VERSION 5.4 ;
NAMESCASESENSITIVE ON ;
BUSBITCHARS "[]" ;
DIVIDERCHAR "/" ;
UNITS
  DATABASE MICRONS 2000 ;
END UNITS
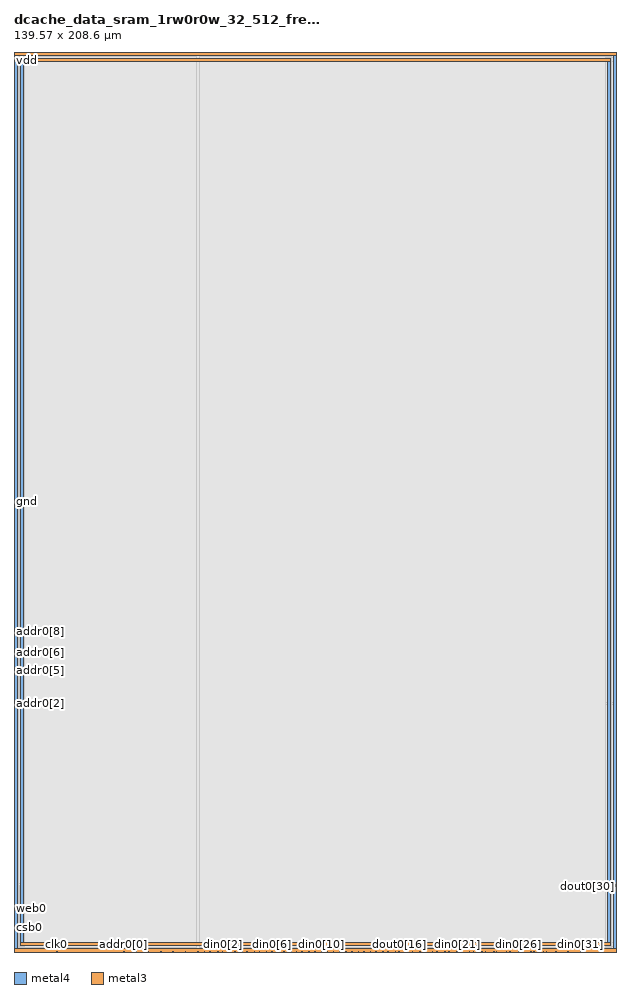
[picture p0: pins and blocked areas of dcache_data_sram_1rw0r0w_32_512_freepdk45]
MACRO dcache_data_sram_1rw0r0w_32_512_freepdk45
   CLASS BLOCK ;
   SIZE 139.57 BY 208.6 ;
   SYMMETRY X Y R90 ;
   PIN din0[0]
      DIRECTION INPUT ;
      PORT
         LAYER metal4 ;
         RECT  42.5575 0.0 42.6975 0.14 ;
      END
   END din0[0]
   PIN din0[1]
      DIRECTION INPUT ;
      PORT
         LAYER metal4 ;
         RECT  45.4175 0.0 45.5575 0.14 ;
      END
   END din0[1]
   PIN din0[2]
      DIRECTION INPUT ;
      PORT
         LAYER metal4 ;
         RECT  48.2775 0.0 48.4175 0.14 ;
      END
   END din0[2]
   PIN din0[3]
      DIRECTION INPUT ;
      PORT
         LAYER metal4 ;
         RECT  51.1375 0.0 51.2775 0.14 ;
      END
   END din0[3]
   PIN din0[4]
      DIRECTION INPUT ;
      PORT
         LAYER metal4 ;
         RECT  53.9975 0.0 54.1375 0.14 ;
      END
   END din0[4]
   PIN din0[5]
      DIRECTION INPUT ;
      PORT
         LAYER metal4 ;
         RECT  56.8575 0.0 56.9975 0.14 ;
      END
   END din0[5]
   PIN din0[6]
      DIRECTION INPUT ;
      PORT
         LAYER metal4 ;
         RECT  59.7175 0.0 59.8575 0.14 ;
      END
   END din0[6]
   PIN din0[7]
      DIRECTION INPUT ;
      PORT
         LAYER metal4 ;
         RECT  62.5775 0.0 62.7175 0.14 ;
      END
   END din0[7]
   PIN din0[8]
      DIRECTION INPUT ;
      PORT
         LAYER metal4 ;
         RECT  65.4375 0.0 65.5775 0.14 ;
      END
   END din0[8]
   PIN din0[9]
      DIRECTION INPUT ;
      PORT
         LAYER metal4 ;
         RECT  68.2975 0.0 68.4375 0.14 ;
      END
   END din0[9]
   PIN din0[10]
      DIRECTION INPUT ;
      PORT
         LAYER metal4 ;
         RECT  71.1575 0.0 71.2975 0.14 ;
      END
   END din0[10]
   PIN din0[11]
      DIRECTION INPUT ;
      PORT
         LAYER metal4 ;
         RECT  74.0175 0.0 74.1575 0.14 ;
      END
   END din0[11]
   PIN din0[12]
      DIRECTION INPUT ;
      PORT
         LAYER metal4 ;
         RECT  76.8775 0.0 77.0175 0.14 ;
      END
   END din0[12]
   PIN din0[13]
      DIRECTION INPUT ;
      PORT
         LAYER metal4 ;
         RECT  79.7375 0.0 79.8775 0.14 ;
      END
   END din0[13]
   PIN din0[14]
      DIRECTION INPUT ;
      PORT
         LAYER metal4 ;
         RECT  82.5975 0.0 82.7375 0.14 ;
      END
   END din0[14]
   PIN din0[15]
      DIRECTION INPUT ;
      PORT
         LAYER metal4 ;
         RECT  85.4575 0.0 85.5975 0.14 ;
      END
   END din0[15]
   PIN din0[16]
      DIRECTION INPUT ;
      PORT
         LAYER metal4 ;
         RECT  88.3175 0.0 88.4575 0.14 ;
      END
   END din0[16]
   PIN din0[17]
      DIRECTION INPUT ;
      PORT
         LAYER metal4 ;
         RECT  91.1775 0.0 91.3175 0.14 ;
      END
   END din0[17]
   PIN din0[18]
      DIRECTION INPUT ;
      PORT
         LAYER metal4 ;
         RECT  94.0375 0.0 94.1775 0.14 ;
      END
   END din0[18]
   PIN din0[19]
      DIRECTION INPUT ;
      PORT
         LAYER metal4 ;
         RECT  96.8975 0.0 97.0375 0.14 ;
      END
   END din0[19]
   PIN din0[20]
      DIRECTION INPUT ;
      PORT
         LAYER metal4 ;
         RECT  99.7575 0.0 99.8975 0.14 ;
      END
   END din0[20]
   PIN din0[21]
      DIRECTION INPUT ;
      PORT
         LAYER metal4 ;
         RECT  102.6175 0.0 102.7575 0.14 ;
      END
   END din0[21]
   PIN din0[22]
      DIRECTION INPUT ;
      PORT
         LAYER metal4 ;
         RECT  105.4775 0.0 105.6175 0.14 ;
      END
   END din0[22]
   PIN din0[23]
      DIRECTION INPUT ;
      PORT
         LAYER metal4 ;
         RECT  108.3375 0.0 108.4775 0.14 ;
      END
   END din0[23]
   PIN din0[24]
      DIRECTION INPUT ;
      PORT
         LAYER metal4 ;
         RECT  111.1975 0.0 111.3375 0.14 ;
      END
   END din0[24]
   PIN din0[25]
      DIRECTION INPUT ;
      PORT
         LAYER metal4 ;
         RECT  114.0575 0.0 114.1975 0.14 ;
      END
   END din0[25]
   PIN din0[26]
      DIRECTION INPUT ;
      PORT
         LAYER metal4 ;
         RECT  116.9175 0.0 117.0575 0.14 ;
      END
   END din0[26]
   PIN din0[27]
      DIRECTION INPUT ;
      PORT
         LAYER metal4 ;
         RECT  119.7775 0.0 119.9175 0.14 ;
      END
   END din0[27]
   PIN din0[28]
      DIRECTION INPUT ;
      PORT
         LAYER metal4 ;
         RECT  122.6375 0.0 122.7775 0.14 ;
      END
   END din0[28]
   PIN din0[29]
      DIRECTION INPUT ;
      PORT
         LAYER metal4 ;
         RECT  125.4975 0.0 125.6375 0.14 ;
      END
   END din0[29]
   PIN din0[30]
      DIRECTION INPUT ;
      PORT
         LAYER metal4 ;
         RECT  128.3575 0.0 128.4975 0.14 ;
      END
   END din0[30]
   PIN din0[31]
      DIRECTION INPUT ;
      PORT
         LAYER metal4 ;
         RECT  131.2175 0.0 131.3575 0.14 ;
      END
   END din0[31]
   PIN addr0[0]
      DIRECTION INPUT ;
      PORT
         LAYER metal4 ;
         RECT  25.3975 0.0 25.5375 0.14 ;
      END
   END addr0[0]
   PIN addr0[1]
      DIRECTION INPUT ;
      PORT
         LAYER metal4 ;
         RECT  28.2575 0.0 28.3975 0.14 ;
      END
   END addr0[1]
   PIN addr0[2]
      DIRECTION INPUT ;
      PORT
         LAYER metal3 ;
         RECT  0.0 57.5725 0.14 57.7125 ;
      END
   END addr0[2]
   PIN addr0[3]
      DIRECTION INPUT ;
      PORT
         LAYER metal3 ;
         RECT  0.0 60.3025 0.14 60.4425 ;
      END
   END addr0[3]
   PIN addr0[4]
      DIRECTION INPUT ;
      PORT
         LAYER metal3 ;
         RECT  0.0 62.5125 0.14 62.6525 ;
      END
   END addr0[4]
   PIN addr0[5]
      DIRECTION INPUT ;
      PORT
         LAYER metal3 ;
         RECT  0.0 65.2425 0.14 65.3825 ;
      END
   END addr0[5]
   PIN addr0[6]
      DIRECTION INPUT ;
      PORT
         LAYER metal3 ;
         RECT  0.0 67.4525 0.14 67.5925 ;
      END
   END addr0[6]
   PIN addr0[7]
      DIRECTION INPUT ;
      PORT
         LAYER metal3 ;
         RECT  0.0 70.1825 0.14 70.3225 ;
      END
   END addr0[7]
   PIN addr0[8]
      DIRECTION INPUT ;
      PORT
         LAYER metal3 ;
         RECT  0.0 72.3925 0.14 72.5325 ;
      END
   END addr0[8]
   PIN csb0
      DIRECTION INPUT ;
      PORT
         LAYER metal3 ;
         RECT  0.0 7.3925 0.14 7.5325 ;
      END
   END csb0
   PIN web0
      DIRECTION INPUT ;
      PORT
         LAYER metal3 ;
         RECT  0.0 10.1225 0.14 10.2625 ;
      END
   END web0
   PIN clk0
      DIRECTION INPUT ;
      PORT
         LAYER metal4 ;
         RECT  9.84 0.0 9.98 0.14 ;
      END
   END clk0
   PIN wmask0[0]
      DIRECTION INPUT ;
      PORT
         LAYER metal4 ;
         RECT  31.1175 0.0 31.2575 0.14 ;
      END
   END wmask0[0]
   PIN wmask0[1]
      DIRECTION INPUT ;
      PORT
         LAYER metal4 ;
         RECT  33.9775 0.0 34.1175 0.14 ;
      END
   END wmask0[1]
   PIN wmask0[2]
      DIRECTION INPUT ;
      PORT
         LAYER metal4 ;
         RECT  36.8375 0.0 36.9775 0.14 ;
      END
   END wmask0[2]
   PIN wmask0[3]
      DIRECTION INPUT ;
      PORT
         LAYER metal4 ;
         RECT  39.6975 0.0 39.8375 0.14 ;
      END
   END wmask0[3]
   PIN dout0[0]
      DIRECTION OUTPUT ;
      PORT
         LAYER metal4 ;
         RECT  44.06 0.0 44.2 0.14 ;
      END
   END dout0[0]
   PIN dout0[1]
      DIRECTION OUTPUT ;
      PORT
         LAYER metal4 ;
         RECT  47.1925 0.0 47.3325 0.14 ;
      END
   END dout0[1]
   PIN dout0[2]
      DIRECTION OUTPUT ;
      PORT
         LAYER metal4 ;
         RECT  50.0125 0.0 50.1525 0.14 ;
      END
   END dout0[2]
   PIN dout0[3]
      DIRECTION OUTPUT ;
      PORT
         LAYER metal4 ;
         RECT  52.8325 0.0 52.9725 0.14 ;
      END
   END dout0[3]
   PIN dout0[4]
      DIRECTION OUTPUT ;
      PORT
         LAYER metal4 ;
         RECT  55.6525 0.0 55.7925 0.14 ;
      END
   END dout0[4]
   PIN dout0[5]
      DIRECTION OUTPUT ;
      PORT
         LAYER metal4 ;
         RECT  58.4725 0.0 58.6125 0.14 ;
      END
   END dout0[5]
   PIN dout0[6]
      DIRECTION OUTPUT ;
      PORT
         LAYER metal4 ;
         RECT  61.2925 0.0 61.4325 0.14 ;
      END
   END dout0[6]
   PIN dout0[7]
      DIRECTION OUTPUT ;
      PORT
         LAYER metal4 ;
         RECT  64.1125 0.0 64.2525 0.14 ;
      END
   END dout0[7]
   PIN dout0[8]
      DIRECTION OUTPUT ;
      PORT
         LAYER metal4 ;
         RECT  66.62 0.0 66.76 0.14 ;
      END
   END dout0[8]
   PIN dout0[9]
      DIRECTION OUTPUT ;
      PORT
         LAYER metal4 ;
         RECT  69.7525 0.0 69.8925 0.14 ;
      END
   END dout0[9]
   PIN dout0[10]
      DIRECTION OUTPUT ;
      PORT
         LAYER metal4 ;
         RECT  72.5725 0.0 72.7125 0.14 ;
      END
   END dout0[10]
   PIN dout0[11]
      DIRECTION OUTPUT ;
      PORT
         LAYER metal4 ;
         RECT  75.3925 0.0 75.5325 0.14 ;
      END
   END dout0[11]
   PIN dout0[12]
      DIRECTION OUTPUT ;
      PORT
         LAYER metal4 ;
         RECT  78.2125 0.0 78.3525 0.14 ;
      END
   END dout0[12]
   PIN dout0[13]
      DIRECTION OUTPUT ;
      PORT
         LAYER metal4 ;
         RECT  81.0325 0.0 81.1725 0.14 ;
      END
   END dout0[13]
   PIN dout0[14]
      DIRECTION OUTPUT ;
      PORT
         LAYER metal4 ;
         RECT  83.8525 0.0 83.9925 0.14 ;
      END
   END dout0[14]
   PIN dout0[15]
      DIRECTION OUTPUT ;
      PORT
         LAYER metal4 ;
         RECT  86.6725 0.0 86.8125 0.14 ;
      END
   END dout0[15]
   PIN dout0[16]
      DIRECTION OUTPUT ;
      PORT
         LAYER metal4 ;
         RECT  89.18 0.0 89.32 0.14 ;
      END
   END dout0[16]
   PIN dout0[17]
      DIRECTION OUTPUT ;
      PORT
         LAYER metal4 ;
         RECT  92.3125 0.0 92.4525 0.14 ;
      END
   END dout0[17]
   PIN dout0[18]
      DIRECTION OUTPUT ;
      PORT
         LAYER metal4 ;
         RECT  95.1325 0.0 95.2725 0.14 ;
      END
   END dout0[18]
   PIN dout0[19]
      DIRECTION OUTPUT ;
      PORT
         LAYER metal4 ;
         RECT  97.9525 0.0 98.0925 0.14 ;
      END
   END dout0[19]
   PIN dout0[20]
      DIRECTION OUTPUT ;
      PORT
         LAYER metal4 ;
         RECT  100.7725 0.0 100.9125 0.14 ;
      END
   END dout0[20]
   PIN dout0[21]
      DIRECTION OUTPUT ;
      PORT
         LAYER metal4 ;
         RECT  103.5925 0.0 103.7325 0.14 ;
      END
   END dout0[21]
   PIN dout0[22]
      DIRECTION OUTPUT ;
      PORT
         LAYER metal4 ;
         RECT  106.4125 0.0 106.5525 0.14 ;
      END
   END dout0[22]
   PIN dout0[23]
      DIRECTION OUTPUT ;
      PORT
         LAYER metal4 ;
         RECT  109.2325 0.0 109.3725 0.14 ;
      END
   END dout0[23]
   PIN dout0[24]
      DIRECTION OUTPUT ;
      PORT
         LAYER metal4 ;
         RECT  111.74 0.0 111.88 0.14 ;
      END
   END dout0[24]
   PIN dout0[25]
      DIRECTION OUTPUT ;
      PORT
         LAYER metal4 ;
         RECT  114.8725 0.0 115.0125 0.14 ;
      END
   END dout0[25]
   PIN dout0[26]
      DIRECTION OUTPUT ;
      PORT
         LAYER metal4 ;
         RECT  117.6925 0.0 117.8325 0.14 ;
      END
   END dout0[26]
   PIN dout0[27]
      DIRECTION OUTPUT ;
      PORT
         LAYER metal4 ;
         RECT  120.5125 0.0 120.6525 0.14 ;
      END
   END dout0[27]
   PIN dout0[28]
      DIRECTION OUTPUT ;
      PORT
         LAYER metal4 ;
         RECT  123.3325 0.0 123.4725 0.14 ;
      END
   END dout0[28]
   PIN dout0[29]
      DIRECTION OUTPUT ;
      PORT
         LAYER metal3 ;
         RECT  139.43 15.555 139.57 15.695 ;
      END
   END dout0[29]
   PIN dout0[30]
      DIRECTION OUTPUT ;
      PORT
         LAYER metal3 ;
         RECT  139.43 15.085 139.57 15.225 ;
      END
   END dout0[30]
   PIN dout0[31]
      DIRECTION OUTPUT ;
      PORT
         LAYER metal3 ;
         RECT  139.43 15.32 139.57 15.46 ;
      END
   END dout0[31]
   PIN vdd
      DIRECTION INOUT ;
      USE POWER ; 
      SHAPE ABUTMENT ; 
      PORT
         LAYER metal4 ;
         RECT  138.87 0.0 139.57 208.6 ;
         LAYER metal3 ;
         RECT  0.0 0.0 139.57 0.7 ;
         LAYER metal3 ;
         RECT  0.0 207.9 139.57 208.6 ;
         LAYER metal4 ;
         RECT  0.0 0.0 0.7 208.6 ;
      END
   END vdd
   PIN gnd
      DIRECTION INOUT ;
      USE GROUND ; 
      SHAPE ABUTMENT ; 
      PORT
         LAYER metal3 ;
         RECT  1.4 1.4 138.17 2.1 ;
         LAYER metal3 ;
         RECT  1.4 206.5 138.17 207.2 ;
         LAYER metal4 ;
         RECT  1.4 1.4 2.1 207.2 ;
         LAYER metal4 ;
         RECT  137.47 1.4 138.17 207.2 ;
      END
   END gnd
   OBS
   LAYER  metal1 ;
      RECT  0.14 0.14 139.43 208.46 ;
   LAYER  metal2 ;
      RECT  0.14 0.14 139.43 208.46 ;
   LAYER  metal3 ;
      RECT  0.28 57.4325 139.43 57.8525 ;
      RECT  0.14 57.8525 0.28 60.1625 ;
      RECT  0.14 60.5825 0.28 62.3725 ;
      RECT  0.14 62.7925 0.28 65.1025 ;
      RECT  0.14 65.5225 0.28 67.3125 ;
      RECT  0.14 67.7325 0.28 70.0425 ;
      RECT  0.14 70.4625 0.28 72.2525 ;
      RECT  0.14 7.6725 0.28 9.9825 ;
      RECT  0.14 10.4025 0.28 57.4325 ;
      RECT  0.28 15.415 139.29 15.835 ;
      RECT  0.28 15.835 139.29 57.4325 ;
      RECT  139.29 15.835 139.43 57.4325 ;
      RECT  0.14 0.84 0.28 7.2525 ;
      RECT  139.29 0.84 139.43 14.945 ;
      RECT  0.14 72.6725 0.28 207.76 ;
      RECT  0.28 0.84 1.26 1.26 ;
      RECT  0.28 1.26 1.26 2.24 ;
      RECT  0.28 2.24 1.26 15.415 ;
      RECT  1.26 0.84 138.31 1.26 ;
      RECT  1.26 2.24 138.31 15.415 ;
      RECT  138.31 0.84 139.29 1.26 ;
      RECT  138.31 1.26 139.29 2.24 ;
      RECT  138.31 2.24 139.29 15.415 ;
      RECT  0.28 57.8525 1.26 206.36 ;
      RECT  0.28 206.36 1.26 207.34 ;
      RECT  0.28 207.34 1.26 207.76 ;
      RECT  1.26 57.8525 138.31 206.36 ;
      RECT  1.26 207.34 138.31 207.76 ;
      RECT  138.31 57.8525 139.43 206.36 ;
      RECT  138.31 206.36 139.43 207.34 ;
      RECT  138.31 207.34 139.43 207.76 ;
   LAYER  metal4 ;
      RECT  42.2775 0.42 42.9775 208.46 ;
      RECT  125.9175 0.14 128.0775 0.42 ;
      RECT  128.7775 0.14 130.9375 0.42 ;
      RECT  25.8175 0.14 27.9775 0.42 ;
      RECT  10.26 0.14 25.1175 0.42 ;
      RECT  28.6775 0.14 30.8375 0.42 ;
      RECT  31.5375 0.14 33.6975 0.42 ;
      RECT  34.3975 0.14 36.5575 0.42 ;
      RECT  37.2575 0.14 39.4175 0.42 ;
      RECT  40.1175 0.14 42.2775 0.42 ;
      RECT  42.9775 0.14 43.78 0.42 ;
      RECT  44.48 0.14 45.1375 0.42 ;
      RECT  45.8375 0.14 46.9125 0.42 ;
      RECT  47.6125 0.14 47.9975 0.42 ;
      RECT  48.6975 0.14 49.7325 0.42 ;
      RECT  50.4325 0.14 50.8575 0.42 ;
      RECT  51.5575 0.14 52.5525 0.42 ;
      RECT  53.2525 0.14 53.7175 0.42 ;
      RECT  54.4175 0.14 55.3725 0.42 ;
      RECT  56.0725 0.14 56.5775 0.42 ;
      RECT  57.2775 0.14 58.1925 0.42 ;
      RECT  58.8925 0.14 59.4375 0.42 ;
      RECT  60.1375 0.14 61.0125 0.42 ;
      RECT  61.7125 0.14 62.2975 0.42 ;
      RECT  62.9975 0.14 63.8325 0.42 ;
      RECT  64.5325 0.14 65.1575 0.42 ;
      RECT  65.8575 0.14 66.34 0.42 ;
      RECT  67.04 0.14 68.0175 0.42 ;
      RECT  68.7175 0.14 69.4725 0.42 ;
      RECT  70.1725 0.14 70.8775 0.42 ;
      RECT  71.5775 0.14 72.2925 0.42 ;
      RECT  72.9925 0.14 73.7375 0.42 ;
      RECT  74.4375 0.14 75.1125 0.42 ;
      RECT  75.8125 0.14 76.5975 0.42 ;
      RECT  77.2975 0.14 77.9325 0.42 ;
      RECT  78.6325 0.14 79.4575 0.42 ;
      RECT  80.1575 0.14 80.7525 0.42 ;
      RECT  81.4525 0.14 82.3175 0.42 ;
      RECT  83.0175 0.14 83.5725 0.42 ;
      RECT  84.2725 0.14 85.1775 0.42 ;
      RECT  85.8775 0.14 86.3925 0.42 ;
      RECT  87.0925 0.14 88.0375 0.42 ;
      RECT  88.7375 0.14 88.9 0.42 ;
      RECT  89.6 0.14 90.8975 0.42 ;
      RECT  91.5975 0.14 92.0325 0.42 ;
      RECT  92.7325 0.14 93.7575 0.42 ;
      RECT  94.4575 0.14 94.8525 0.42 ;
      RECT  95.5525 0.14 96.6175 0.42 ;
      RECT  97.3175 0.14 97.6725 0.42 ;
      RECT  98.3725 0.14 99.4775 0.42 ;
      RECT  100.1775 0.14 100.4925 0.42 ;
      RECT  101.1925 0.14 102.3375 0.42 ;
      RECT  103.0375 0.14 103.3125 0.42 ;
      RECT  104.0125 0.14 105.1975 0.42 ;
      RECT  105.8975 0.14 106.1325 0.42 ;
      RECT  106.8325 0.14 108.0575 0.42 ;
      RECT  108.7575 0.14 108.9525 0.42 ;
      RECT  109.6525 0.14 110.9175 0.42 ;
      RECT  112.16 0.14 113.7775 0.42 ;
      RECT  114.4775 0.14 114.5925 0.42 ;
      RECT  115.2925 0.14 116.6375 0.42 ;
      RECT  117.3375 0.14 117.4125 0.42 ;
      RECT  118.1125 0.14 119.4975 0.42 ;
      RECT  120.1975 0.14 120.2325 0.42 ;
      RECT  120.9325 0.14 122.3575 0.42 ;
      RECT  123.7525 0.14 125.2175 0.42 ;
      RECT  131.6375 0.14 138.59 0.42 ;
      RECT  0.98 0.14 9.56 0.42 ;
      RECT  0.98 0.42 1.12 1.12 ;
      RECT  0.98 1.12 1.12 207.48 ;
      RECT  0.98 207.48 1.12 208.46 ;
      RECT  1.12 0.42 2.38 1.12 ;
      RECT  1.12 207.48 2.38 208.46 ;
      RECT  2.38 0.42 42.2775 1.12 ;
      RECT  2.38 1.12 42.2775 207.48 ;
      RECT  2.38 207.48 42.2775 208.46 ;
      RECT  42.9775 0.42 137.19 1.12 ;
      RECT  42.9775 1.12 137.19 207.48 ;
      RECT  42.9775 207.48 137.19 208.46 ;
      RECT  137.19 0.42 138.45 1.12 ;
      RECT  137.19 207.48 138.45 208.46 ;
      RECT  138.45 0.42 138.59 1.12 ;
      RECT  138.45 1.12 138.59 207.48 ;
      RECT  138.45 207.48 138.59 208.46 ;
   END
END    dcache_data_sram_1rw0r0w_32_512_freepdk45
END    LIBRARY
